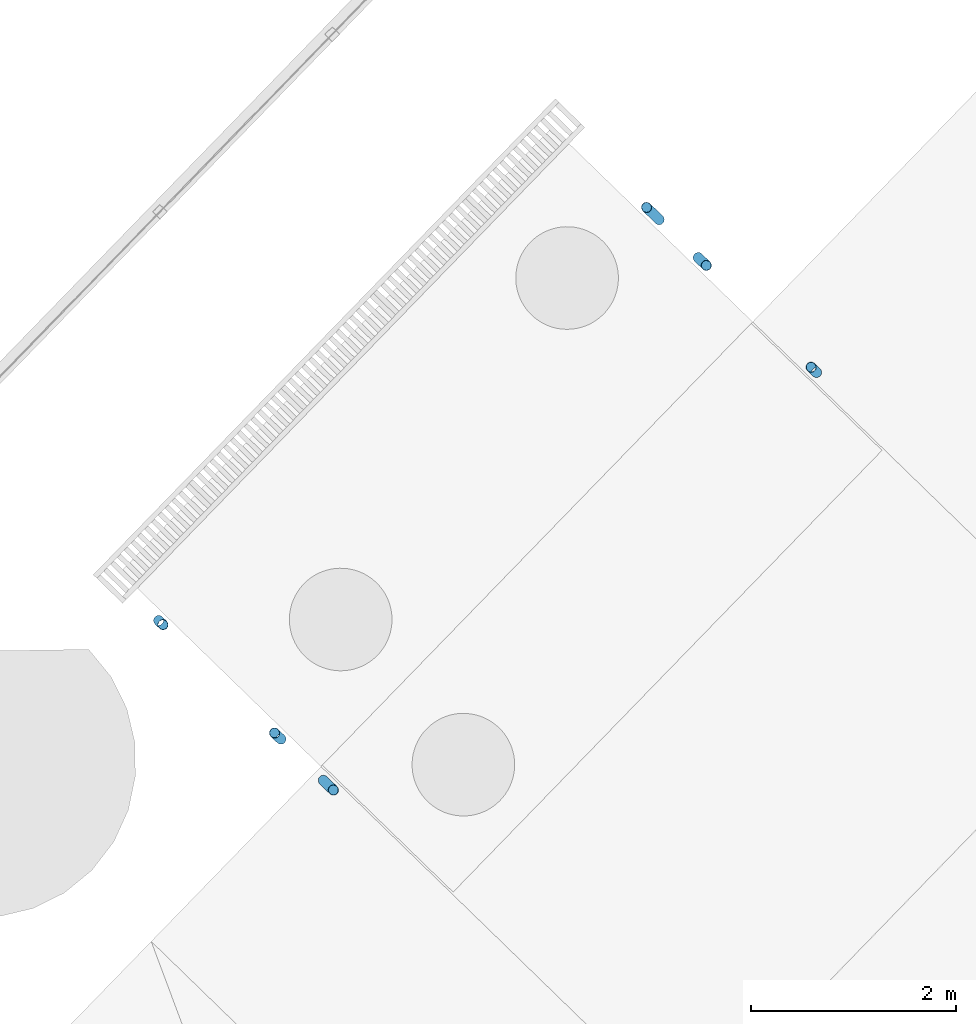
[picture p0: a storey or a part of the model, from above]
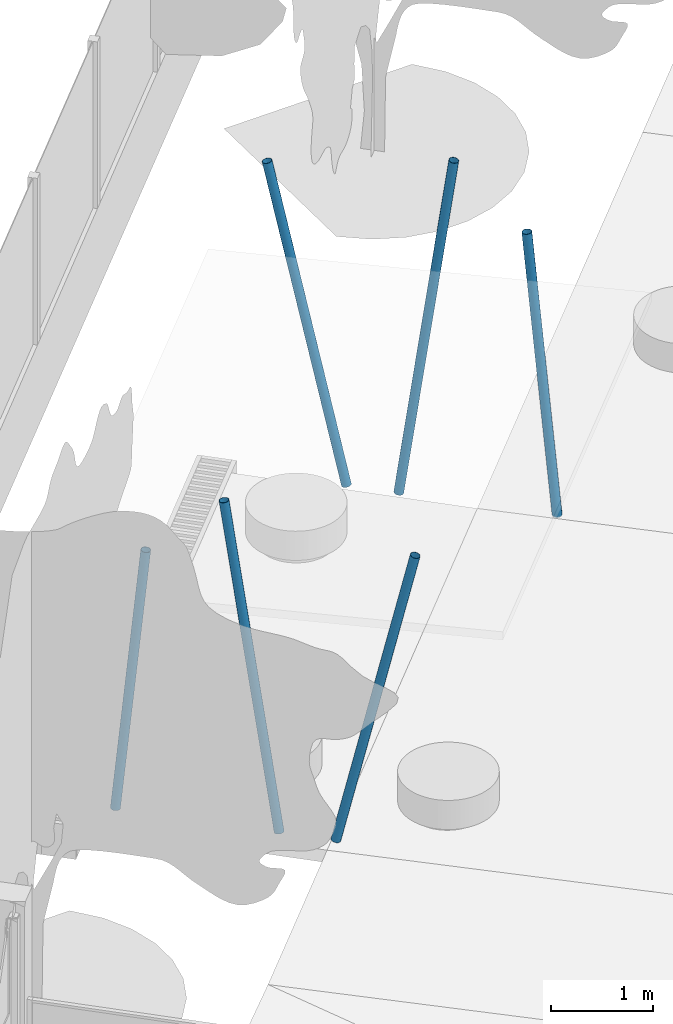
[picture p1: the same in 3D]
Properties of the parts of a building model (IFC2X3)

# File
Description: ViewDefinition [CoordinationView_V2.0]
File name: Número de Proyecto
Time: 2019-11-12T12:35:07
Written by: The EXPRESS Data Manager Version 5.02.0100.07 : 28 Aug 2013
Made in: 20170223_1515(x64) - Exporter 18.0.0.420 - Alternate UI 18.0.0.420
Comment: STEP Physical File produced by: The EXPRESS Data Manager Version 5.02.0100.07 : 28 Aug 2013 * Module: EDMstepFileFactory/EDMstandAlone * Creation date: Tue Nov 12 12:35:07 2019 * Host: DESKTOP-60B30O4 * Database: C:\Users\gerso\AppData\Local\Temp\{02A058CF-D0DC-40C9-913D-C115A4009833}\ifc * Database version: 5507 * Database creation date: Tue Nov 12 12:35:02 2019 * Schema: IFC2X3 * Model: DataRepository.ifc * Model creation date: Tue Nov 12 12:35:02 2019 * Header model: DataRepository.ifc_HeaderModel * Header model creation date: Tue Nov 12 12:35:02 2019 * EDMuser: sdai-user * EDMgroup: sdai-group * License ID and type: 5605 : Permanent license. Expiry date: * EDMstepFileFactory options: 020000

# IfcProject, Número de Proyecto
LongName: CAIF AEROPARQUE, CANELONES; Phase: Project Status

# IfcSite, Surface:4830110
RefLatitude: 42, 24, 53, 508911; RefLongitude: -71, -15, -29, -58837; RefElevation: 0 cm

# IfcBuilding
Pset_BuildingCommon - NumberOfStoreys: 1

# IfcBuildingStorey, Nivel 0.00
LongName: Nivel 0.00; Elevation: 0 cm

# IfcBeam: VIGA_DOBLE T-140mm, M_Double C-Channel:VIGA_DOBLE T-140mm:5060763
In: Nivel 0.00
Type - ElementType: VIGA_DOBLE T-140mm; PredefinedType: BEAM; Classification: B10 Superstructure (Uniformat); Material: Steel, 45-345
Pset_BeamCommon - IsExternal: no; LoadBearing: yes; Reference: VIGA_DOBLE T-140mm; Span: 285.281 cm; Slope: 0 deg

# IfcBuildingElementProxy: ARQ_BANCA_PADRES (2)
In: Nivel 0.00
Pset_BuildingElementProxyCommon - Reference: ARQ_BANCA_PADRES
Name (ARQ_BANCA_PADRES:ARQ_BANCA_PADRES:...)
4937770
4937879

# IfcBuildingElementProxy: ARQ_BANCA_REDONDA (6)
In: Nivel 0.00
Type - Material: Concrete, Precast
Pset_BuildingElementProxyCommon - Reference: ARQ_BANCA_REDONDA
Name (ARQ_BANCA_REDONDA:ARQ_BANCA_REDONDA:...)
4920649
4920650
4920651
4920652
4920653
4920654

# IfcBuildingElementProxy: Liquidambar - 6000mm (8)
In: Nivel 0.00
Pset_BuildingElementProxyCommon - Reference: Liquidambar - 6000mm
Name (M_RPC Tree - Deciduous:Liquidambar - 6000mm:...)
4950376
4950471
4950626
4950713
4950850
4950985
4951068
4951135

# IfcColumn: 114.3x3CHS, CHS-Circular Hollow Section-Column:114.3x3CHS:4920624
In: Nivel 0.00
Type - ElementType: 114.3x3CHS; PredefinedType: COLUMN; Material: METAL_AMARILLO
Pset_ColumnCommon - IsExternal: no; Reference: 114.3x3CHS; LoadBearing: yes; Slope: 1.4168 deg

# IfcColumn: 114.3x3CHS, CHS-Circular Hollow Section-Column:114.3x3CHS:4920618
In: Nivel 0.00
Type - ElementType: 114.3x3CHS; PredefinedType: COLUMN; Material: METAL_CELESTE
Pset_ColumnCommon - IsExternal: no; Reference: 114.3x3CHS; LoadBearing: yes; Slope: 0.584661 deg

# IfcColumn: 114.3x3CHS, CHS-Circular Hollow Section-Column:114.3x3CHS:4920631
In: Nivel 0.00
Type - ElementType: 114.3x3CHS; PredefinedType: COLUMN; Material: METAL_NARANJO
Pset_ColumnCommon - IsExternal: no; Reference: 114.3x3CHS; LoadBearing: yes; Slope: 1.27455 deg

# IfcColumn: 114.3x3CHS, CHS-Circular Hollow Section-Column:114.3x3CHS:4920637
In: Nivel 0.00
Type - ElementType: 114.3x3CHS; PredefinedType: COLUMN; Material: METAL_ROJO
Pset_ColumnCommon - IsExternal: no; Reference: 114.3x3CHS; LoadBearing: yes; Slope: 0.240287 deg

# IfcColumn: 114.3x3CHS, CHS-Circular Hollow Section-Column:114.3x3CHS:4920643
In: Nivel 0.00
Type - ElementType: 114.3x3CHS; PredefinedType: COLUMN; Material: METAL_ROSA
Pset_ColumnCommon - IsExternal: no; Reference: 114.3x3CHS; LoadBearing: yes; Slope: 0.529517 deg

# IfcColumn: 114.3x3CHS, CHS-Circular Hollow Section-Column:114.3x3CHS:4920611
In: Nivel 0.00
Type - ElementType: 114.3x3CHS; PredefinedType: COLUMN; Material: METAL_VERDE
Pset_ColumnCommon - IsExternal: no; Reference: 114.3x3CHS; LoadBearing: yes; Slope: 0.271545 deg

# IfcCurtainWall: Curtain Wall:PORTON_REJA_CIERRE (2)
In: Nivel 0.00
Pset_CurtainWallCommon - IsExternal: no; Reference: PORTON_REJA_CIERRE
Name (Curtain Wall:PORTON_REJA_CIERRE:...)
4990812
5004357

# IfcCurtainWall: Curtain Wall:PORTON_REJA_CIERRE_3, Curtain Wall:PORTON_REJA_CIERRE_3:4997292
In: Nivel 0.00
Pset_CurtainWallCommon - IsExternal: no; Reference: PORTON_REJA_CIERRE_3

# IfcCurtainWall: Curtain Wall:REJA_BAJA_100mm (5)
In: Nivel 0.00
Pset_CurtainWallCommon - IsExternal: no; Reference: REJA_BAJA_100mm
Name (Curtain Wall:REJA_BAJA_100mm:...)
4925248
5006986
5008714
5012567
5013677

# IfcCurtainWall: Curtain Wall:REJA_BAJA_SIMPLE_100mm (3)
In: Nivel 0.00
Pset_CurtainWallCommon - IsExternal: no; Reference: REJA_BAJA_SIMPLE_100mm
Name (Curtain Wall:REJA_BAJA_SIMPLE_100mm:...)
5012822
5013193
5013416

# IfcDistributionPort (2)
Description: Flow; FlowDirection: SOURCEANDSINK; Group: Hydronic Supply 1
Name
InPort_5035273
OutPort_5040535

# IfcDoor: PORTON_REJA, PORTON_REJA:PORTON_REJA:4990813
In: Nivel 0.00
Type - OperationType: DOUBLE_DOOR_DOUBLE_SWING; ParameterTakesPrecedence: no; Sizeable: no; Classification: B2030100 Glazed Doors & Entrances (Uniformat); Material: Aluminum, REJA_MALLA_ACMA
Type - PORTON_REJA:PORTON_REJA:4990813 - PanelOperation: DOUBLE_ACTING
OverallHeight: 210.013 cm; OverallWidth: 258.469 cm
Pset_DoorCommon - IsExternal: yes; Reference: PORTON_REJA; ThermalTransmittance: 4.11674 kg/K/s3

# IfcDoor: PORTON_REJA, PORTON_REJA:PORTON_REJA:4997297
In: Nivel 0.00
Type - OperationType: DOUBLE_DOOR_DOUBLE_SWING; ParameterTakesPrecedence: no; Sizeable: no; Classification: B2030100 Glazed Doors & Entrances (Uniformat); Material: Aluminum, REJA_MALLA_ACMA
Type - PORTON_REJA:PORTON_REJA:4997297 - PanelOperation: DOUBLE_ACTING
OverallHeight: 210.013 cm; OverallWidth: 155.313 cm
Pset_DoorCommon - IsExternal: yes; Reference: PORTON_REJA; ThermalTransmittance: 4.11674 kg/K/s3

# IfcDoor: PORTON_REJA_baja, PORTON_REJA_baja:PORTON_REJA_baja:5004358
In: Nivel 0.00
Type - ParameterTakesPrecedence: no; Sizeable: no; Classification: B2030100 Glazed Doors & Entrances (Uniformat); Material: Aluminum, REJA_MALLA_ACMA
OverallHeight: 93.0131 cm; OverallWidth: 174.015 cm
Pset_DoorCommon - IsExternal: yes; Reference: PORTON_REJA_baja; ThermalTransmittance: 4.11674 kg/K/s3

# IfcDoor: PUERTA_REJA, PUERTA_REJA:PUERTA_REJA:4997293
In: Nivel 0.00
Type - ParameterTakesPrecedence: no; Sizeable: no; Classification: B2030100 Glazed Doors & Entrances (Uniformat); Material: REJA_MALLA_ACMA, Aluminum
OverallHeight: 210 cm; OverallWidth: 99.9767 cm
Pset_DoorCommon - IsExternal: yes; Reference: PUERTA_REJA

# IfcDoor: PUERTA_REJA_BAJA (4)
In: Nivel 0.00
Type - ParameterTakesPrecedence: no; Sizeable: no; Classification: B2030100 Glazed Doors & Entrances (Uniformat); Material: REJA_MALLA_ACMA, Aluminum
Pset_DoorCommon - IsExternal: yes; Reference: PUERTA_REJA_BAJA
Name (PUERTA_REJA_BAJA:PUERTA_REJA_BAJA:...) | OverallHeight (cm) | OverallWidth (cm)
4925249 | 100 | 69.9175
5006987 | 100 | 64.9902
5008719 | 100 | 64.9787
5013417 | 98 | 83.5751

# IfcFlowFitting: Standard (4)
In: Nivel 0.00
Type - Material: PVC-Piping
Pset_DistributionFlowElementCommon - Reference: Standard
Name (M_Coupling - PVC - Sch 40:Standard:...)
5035751
5040502
5040535 | Group: Hydronic Supply 1
5040545

# IfcFlowSegment: Pipe Types:TUBERIA_PVC (2)
In: Nivel 0.00
Pset_DistributionFlowElementCommon - Reference: TUBERIA_PVC
Name (Pipe Types:TUBERIA_PVC:...)
5035273 | Group: Hydronic Supply 1
5039971

# IfcFurnishingElement: ARQ_MODULO_JAULA (4)
In: Nivel 0.00
Type - ElementType: ARQ_MODULO_JAULA; Material: REJA_MALLA, Aluminum
Name (ARQ_MODULO_JAULA:ARQ_MODULO_JAULA:...)
4924644
4924795
4924817
4924843

# IfcFurnishingElement: ARQ_NICHOS, ARQ_NICHOS:ARQ_NICHOS:5019001
In: Nivel 0.00
Type - ElementType: ARQ_NICHOS

# IfcMember: Curtain Wall:PORTON_REJA_CIERRE_3:4997060 (3)
In: Nivel 0.00
Material: Aluminum
Pset_MemberCommon - IsExternal: no; LoadBearing: yes; Reference: ARQ_REJA_PILAR_100x100mm; Span: 210 cm

# IfcMember: Curtain Wall:REJA_BAJA_100mm:5004744 (20)
In: Nivel 0.00
Material: Aluminum
Pset_MemberCommon - IsExternal: no; LoadBearing: yes; Reference: ARQ_REJA_MULL_50x30mm
Name (Curtain Wall:REJA_BAJA_100mm:...) | Span (cm)
2 x 5004744 | 87.6675
2 x 5004744 | 90.4175
2 x 5004744 | 330.23
2 x 5004744 | 523.041
2 x 5004744 | 77.3537
4 x 5004744 | 184
6 x 5004744 | 162.333

# IfcMember: Curtain Wall:REJA_BAJA_100mm:5004746 (18)
In: Nivel 0.00
Material: Aluminum
Pset_MemberCommon - IsExternal: no; LoadBearing: yes; Reference: ARQ_REJA_MULL_50x50mm
Name (Curtain Wall:REJA_BAJA_100mm:...) | Span (cm)
11 x 5004746 | 100
7 x 5004746 | 98

# IfcMember: Curtain Wall:REJA_BAJA_SIMPLE_100mm:5004744 (4)
In: Nivel 0.00
Material: Aluminum
Pset_MemberCommon - IsExternal: no; LoadBearing: yes; Reference: ARQ_REJA_MULL_50x30mm
Name (Curtain Wall:REJA_BAJA_SIMPLE_100mm:...) | Span (cm)
2 x 5004744 | 88.5751
2 x 5004744 | 95.0764

# IfcMember: Curtain Wall:REJA_BAJA_SIMPLE_100mm:5004746 (6)
In: Nivel 0.00
Material: Aluminum
Pset_MemberCommon - IsExternal: no; LoadBearing: yes; Reference: ARQ_REJA_MULL_50x50mm; Span: 98 cm

# IfcPlate: MALLA ACMA (12)
In: Nivel 0.00
Type - ElementType: MALLA ACMA; PredefinedType: CURTAIN_PANEL; Material: REJA_MALLA_ACMA
Pset_PlateCommon - IsExternal: no; LoadBearing: yes; Reference: MALLA ACMA
Name (System Panel:MALLA ACMA:...)
4925254
4925813
5006992
5008715
5008721
5012568
5012572
5012823
5013194
5013678
5013681
5013910

# IfcRailing: Railing:BARANDA_ESCALA_EXT_950mm, Railing:BARANDA_ESCALA_EXT_950mm:4849142
In: Nivel 0.00
Material: Aluminum
Pset_RailingCommon - IsExternal: no; Reference: BARANDA_ESCALA_EXT_950mm; Height: 45 cm

# IfcRailing: Railing:BARANDA_RAMPA_1000mm (6)
In: Nivel 0.00
Material: Aluminum
Pset_RailingCommon - IsExternal: no; Reference: BARANDA_RAMPA_1000mm; Height: 100 cm
Name (Railing:BARANDA_RAMPA_1000mm:...)
4845272
4848528
4848613
4848921
4920715
4920767

# IfcRailing: Railing:REJA_PERIMETRAL_2000mm (4)
In: Nivel 0.00
Material: REJA_MALLA_ACMA, Aluminum
Pset_RailingCommon - IsExternal: no; Reference: REJA_PERIMETRAL_2000mm; Height: 100 cm
Name (Railing:REJA_PERIMETRAL_2000mm:...)
4932604
4933910
4935197
4935754

# IfcRailing: Railing:REJA_PERIMETRAL_S-PILAR_2000mm (2)
In: Nivel 0.00
Material: REJA_MALLA_ACMA, Aluminum
Pset_RailingCommon - IsExternal: no; Reference: REJA_PERIMETRAL_S-PILAR_2000mm; Height: 100 cm
Name (Railing:REJA_PERIMETRAL_S-PILAR_2000mm:...)
4935406
4935630

# IfcRailing: Railing:REJA_PERIMETRAL_SEG_2000mm, Railing:REJA_PERIMETRAL_SEG_2000mm:5001941
In: Nivel 0.00
Material: REJA_MALLA_ACMA, Aluminum
Pset_RailingCommon - IsExternal: no; Reference: REJA_PERIMETRAL_SEG_2000mm; Height: 100 cm

# IfcSlab: Floor:ARQ_LOSA_HOMRIGON_100mm (4)
In: Nivel 0.00
PredefinedType: FLOOR; Material: Concrete, Precast 10 cm
Pset_SlabCommon - IsExternal: no; LoadBearing: no; PitchAngle: 0 deg; Reference: ARQ_LOSA_HOMRIGON_100mm; ThermalTransmittance: 10.46 kg/K/s3
Name (Floor:ARQ_LOSA_HOMRIGON_100mm:...)
4920605
4943063
4943092
4943118

# IfcSlab: Pad:HORMIGON_EXTERIOR_100mm, Pad:HORMIGON_EXTERIOR_100mm:4837906
In: Nivel 0.00
PredefinedType: FLOOR; Material: <Unnamed> 10 cm
Pset_SlabCommon - IsExternal: no; Reference: HORMIGON_EXTERIOR_100mm

# IfcSlab: Pad:HORMIGON_EXTERIOR_150mm (64)
In: Nivel 0.00
PredefinedType: FLOOR; Material: <Unnamed> 15 cm
Pset_SlabCommon - Reference: HORMIGON_EXTERIOR_150mm; IsExternal: no
Name (Pad:HORMIGON_EXTERIOR_150mm:...)
4831781
4831809
4831837
4831863
4831889
4831917
4831945
4831973
4832009
4832037
4832065
4832207
4832236
4832443
4832488
4832667
4832731
4832836
4832868
4833029
4833050
4833157
4833259
4833400
4833488
4833581
4833693
4833834
4833949
4833994
4834112
4834222
4834343
4834373
4834498
4834527
4834579
4834697
4834798
4834938
4835034
4835067
4835182
4835289
4835424
4835444
4835465
4835673
4835797
4835897
4836003
4836123
4836153
4836367
4836469
4836523
4836653
4836704
4836800
4836899
4836927
4837988
4838151
5038247

# IfcSlab: Pad:HORMIGON_M.CONTEN_1000mm (9)
In: Nivel 0.00
PredefinedType: FLOOR; Material: Concrete, Cast-in-Place gray 100 cm
Pset_SlabCommon - IsExternal: no; Reference: HORMIGON_M.CONTEN_1000mm; ThermalTransmittance: 1.046 kg/K/s3
Name (Pad:HORMIGON_M.CONTEN_1000mm:...)
5021600
5022528
5022807
5022868
5023022
5023130
5023373
5023460
5038668

# IfcSlab: Pad:HORMIGON_SOBRESUELO_200mm, Pad:HORMIGON_SOBRESUELO_200mm:4836263
In: Nivel 0.00
PredefinedType: FLOOR; Material: <Unnamed> 20 cm
Pset_SlabCommon - IsExternal: no; Reference: HORMIGON_SOBRESUELO_200mm

# IfcSlab: REGUERA_METÁLICA1:REGUERA_METÁLICA-01, REGUERA_METÁLICA1:REGUERA_METÁLICA-01:4919038
In: Nivel 0.00
PredefinedType: FLOOR; Material: Stainless Steel
Pset_SlabCommon - IsExternal: no; Reference: REGUERA_METÁLICA-01; PitchAngle: 0 deg

# IfcSlab: REGUERA_METÁLICA2:REGUERA_METÁLICA-02, REGUERA_METÁLICA2:REGUERA_METÁLICA-02:4919154
In: Nivel 0.00
PredefinedType: FLOOR; Material: Stainless Steel
Pset_SlabCommon - IsExternal: no; PitchAngle: 0 deg; Reference: REGUERA_METÁLICA-02

# IfcSlab: REGUERA_METÁLICA3:REGUERA_METÁLICA-03, REGUERA_METÁLICA3:REGUERA_METÁLICA-03:4919742
In: Nivel 0.00
PredefinedType: FLOOR; Material: Stainless Steel
Pset_SlabCommon - IsExternal: no; PitchAngle: 0 deg; Reference: REGUERA_METÁLICA-03

# IfcSlab: REGUERA_METÁLICA4:REGUERA_METÁLICA-04, REGUERA_METÁLICA4:REGUERA_METÁLICA-04:4920133
In: Nivel 0.00
PredefinedType: FLOOR; Material: Stainless Steel
Pset_SlabCommon - IsExternal: no; PitchAngle: 0 deg; Reference: REGUERA_METÁLICA-04

# IfcSlab: REGUERA_METÁLICA5:REGUERA_METÁLICA-03, REGUERA_METÁLICA5:REGUERA_METÁLICA-03:4943918
In: Nivel 0.00
PredefinedType: FLOOR; Material: Default Roof
Pset_SlabCommon - IsExternal: no; PitchAngle: 0 deg; Reference: REGUERA_METÁLICA-03

# IfcStair: Cast-In-Place Stair:Monolithic Stair:159991 (2)
In: Nivel 0.00
Pset_StairCommon - IsExternal: no; Reference: Monolithic Stair; NumberOfRiser: 12; NumberOfTreads: 11; TreadLength: 27.5 cm
Name (Cast-In-Place Stair:Stair:...) | RiserHeight (cm)
4918851 | 18.1667
4918884 | 18

# IfcStairFlight: Cast-In-Place Stair:Monolithic Stair:159991 (2)
In: Nivel 0.00
NumberOfRiser: 12; NumberOfTreads: 11; TreadLength: 0.902231 cm; Material: Concrete, Cast-in-Place gray
Pset_StairFlightCommon - Reference: 150mm Depth; NumberOfRiser: 12; NumberOfTreads: 11; TreadLength: 27.5 cm; TreadLengthAtOffset: 27.5 cm; NosingLength: 0 cm
Name (Cast-In-Place Stair:Stair:...) | RiserHeight (cm) | Pset_StairFlightCommon, RiserHeight (cm)
4918851 Run 1 | 0.596019 | 18.1667
4918884 Run 1 | 0.590551 | 18

# IfcWall: MURO_NICHO1:MURO_NICHO, MURO_NICHO1:MURO_NICHO:4920674
In: Nivel 0.00
Type - Material: ARQ_AlUMINIO_NEGRO
Pset_WallCommon - IsExternal: no; LoadBearing: no; ExtendToStructure: no; Reference: MURO_NICHO

# IfcWallStandardCase: Basic Wall:ARQ_FND_HA_150mm (14)
In: Nivel 0.00
Type - PredefinedType: STANDARD; Material: Concrete, Cast-in-Place gray 15 cm
Pset_WallCommon - Reference: ARQ_FND_HA_150mm; LoadBearing: no; ExtendToStructure: no; IsExternal: yes; ThermalTransmittance: 6.97333 kg/K/s3
Name (Basic Wall:ARQ_FND_HA_150mm:...)
4918833
4918834
4918835
4918836
4918837
4918838
4918839
4918840
4918917
4918918
4920699
4920700
4920701
4920702

# IfcWallStandardCase: Basic Wall:ARQ_FND_HA_50mm (12)
In: Nivel 0.00
Type - PredefinedType: STANDARD; Material: Concrete, Cast-in-Place gray 5 cm
Pset_WallCommon - LoadBearing: no; ExtendToStructure: no; IsExternal: yes; Reference: ARQ_FND_HA_50mm; ThermalTransmittance: 20.92 kg/K/s3
Name (Basic Wall:ARQ_FND_HA_50mm:...)
4943262
4943364
4943368
4943372
4947274
4947337
4947372
4947373
4947381
4947382
4947392
4947393

# IfcWallStandardCase: Basic Wall:ARQ_FND_LA_150mm (4)
In: Nivel 0.00
Type - PredefinedType: STANDARD; Material: Brick, Common 15 cm
Pset_WallCommon - LoadBearing: no; ExtendToStructure: no; IsExternal: yes; Reference: ARQ_FND_LA_150mm; ThermalTransmittance: 3.6 kg/K/s3
Name (Basic Wall:ARQ_FND_LA_150mm:...)
4918847
4918848
4918849
4918850

# IfcWallStandardCase: Basic Wall:ARQ_MUR_EXT_300mm (2)
In: Nivel 0.00
Type - PredefinedType: STANDARD; Material: Brick, Common 30 cm
Pset_WallCommon - LoadBearing: no; ExtendToStructure: no; IsExternal: yes; Reference: ARQ_MUR_EXT_300mm; ThermalTransmittance: 1.8 kg/K/s3
Name (Basic Wall:ARQ_MUR_EXT_300mm:...)
4918843
4918846

# IfcWindow: CAÑO_500mm, VENTANA_CAÑO_500:CAÑO_500mm:4918845
In: Nivel 0.00
Type - ParameterTakesPrecedence: no; Sizeable: no; Classification: B2020100 Windows (Uniformat); Material: ARQ_AlUMINIO_NEGRO
OverallHeight: 50 cm; OverallWidth: 50 cm
Pset_WindowCommon - IsExternal: yes; Reference: CAÑO_500mm; FireRating: 0.5h

# IfcWindow: CAÑO_900mm, VENTANA_CAÑO_900:CAÑO_900mm:4918844
In: Nivel 0.00
Type - ParameterTakesPrecedence: no; Sizeable: no; Classification: B2020100 Windows (Uniformat); Material: ARQ_AlUMINIO_NEGRO
OverallHeight: 90 cm; OverallWidth: 90 cm
Pset_WindowCommon - IsExternal: yes; Reference: CAÑO_900mm; FireRating: 0.5h
